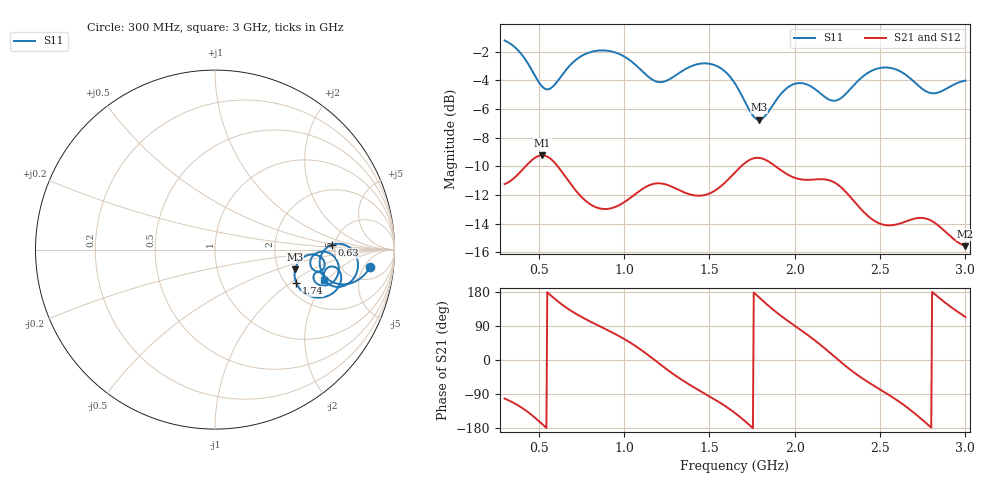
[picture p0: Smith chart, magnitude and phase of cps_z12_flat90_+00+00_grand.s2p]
! cps_z12_flat90_+00+00_grand
! simulated by sim/fixtures_fdtd.py (S12 = S21, S22 not computed)
# HZ S RI R 50
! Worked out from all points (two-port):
!   541 points, 300 MHz to 3 GHz, reference 50 ohm
!   highest |S21| = -9.23 dB at 520 MHz (marker M1); lowest = -15.6 dB at 3 GHz (marker M2)
!   |S21| within 3 dB of the highest: start of sweep to 758.8 MHz; 1.033 GHz to 2.333 GHz (1.3 GHz wide, 77.3 % of centre)
!   lowest |S11| = -6.8 dB at 1.79 GHz (marker M3), VSWR 2.70, Z = 124 - j34.5 ohm
!   |S11| at or under -10 dB: nowhere
!   |S22| runs from - to - dB; largest |S21 - S12| = 0
!   S11 on the Smith chart (normalised r, x): 300 MHz: 9, -7; 630 MHz: 4.68, +0.42; 1.74 GHz: 2.28, -1.12; 3 GHz: 3.30, -1.84
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3e8  0.8633 -0.0987  -0.0553 -0.2686  -0.0553 -0.2686  0 0
4.25e8  0.7146 -0.1937  -0.2184 -0.2301  -0.2184 -0.2301  0 0
5.2e8  0.5897 -0.1114  -0.3391 -0.0656  -0.3391 -0.0656  0 0
6.3e8  0.6495 0.0258  -0.2605 0.1602  -0.2605 0.1602  0 0
7.5e8  0.7667 -0.00378  -0.0999 0.2264  -0.0999 0.2264  0 0
8.85e8  0.794 -0.1122  0.0275 0.2227  0.0275 0.2227  0 0
1.025e9  0.7205 -0.2012  0.1594 0.1829  0.1594 0.1829  0 0
1.2e9  0.6067 -0.1396  0.2737 -0.0355  0.2737 -0.0355  0 0
1.4e9  0.6974 -0.1277  0.0876 -0.2354  0.0876 -0.2354  0 0
1.525e9  0.6802 -0.2197  -0.0555 -0.2526  -0.0555 -0.2526  0 0
1.65e9  0.554 -0.266  -0.2302 -0.1941  -0.2302 -0.1941  0 0
1.74e9  0.4529 -0.1864  -0.332 -0.0361  -0.332 -0.0361  0 0
1.79e9  0.4463 -0.1101  -0.3279 0.0838  -0.3279 0.0838  0 0
1.925e9  0.5698 -0.0313  -0.127 0.2771  -0.127 0.2771  0 0
2.1e9  0.5863 -0.1196  0.1506 0.2408  0.1506 0.2408  0 0
2.26e9  0.5398 -0.043  0.2707 -0.00752  0.2707 -0.00752  0 0
2.38e9  0.6356 -0.0188  0.1648 -0.1563  0.1648 -0.1563  0 0
2.55e9  0.6845 -0.1392  -0.0059 -0.1967  -0.0059 -0.1967  0 0
2.67e9  0.6142 -0.2002  -0.1292 -0.1592  -0.1292 -0.1592  0 0
2.78e9  0.5496 -0.1639  -0.2041 -0.0341  -0.2041 -0.0341  0 0
2.885e9  0.575 -0.1251  -0.1617 0.0927  -0.1617 0.0927  0 0
3e9  0.6065 -0.1682  -0.0662 0.1528  -0.0662 0.1528  0 0
